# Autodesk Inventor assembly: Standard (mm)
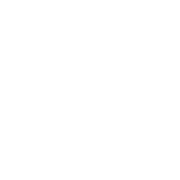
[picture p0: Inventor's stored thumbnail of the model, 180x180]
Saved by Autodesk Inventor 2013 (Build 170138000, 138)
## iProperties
Part Number: Standard (mm)
Document SubType Name: Assembly
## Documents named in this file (1)
- Z:\Vorlagen\Norm.iam
